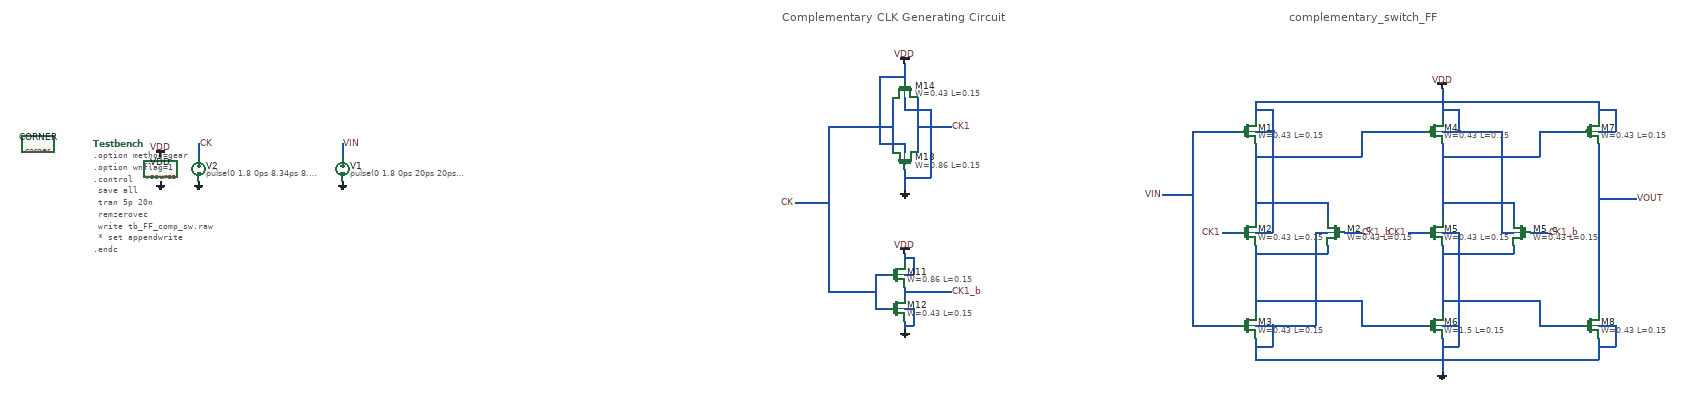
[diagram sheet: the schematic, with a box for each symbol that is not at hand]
v {xschem version=3.4.5 file_version=1.2
}
G {}
K {}
V {}
S {}
E {}
B 2 80 -1250 1130 -1020 {flags=graph
y1=0
y2=1.8
ypos1=0
ypos2=2
divy=5
subdivy=4
unity=1
x1=4.8339884e-10
x2=2.0666956e-09
divx=5
subdivx=4
xlabmag=1.0
ylabmag=1.0


dataset=-1
unitx=1
logx=0
logy=0











linewidth_mult=3





color=6
node=ck}
B 2 80 -990 1130 -760 {flags=graph
y1=0
y2=1.8
ypos1=0
ypos2=2
divy=5
subdivy=4
unity=1
x1=4.8339884e-10
x2=2.0666956e-09
divx=5
subdivx=4
xlabmag=1.0
ylabmag=1.0


dataset=-1
unitx=1
logx=0
logy=0











linewidth_mult=2











color=12
node=vin}
B 2 80 -730 1130 -500 {flags=graph
y1=-0.34
y2=2.2
ypos1=0
ypos2=2
divy=5
subdivy=4
unity=1
x1=4.8339884e-10
x2=2.0666956e-09
divx=5
subdivx=4
xlabmag=1.0
ylabmag=1.0


dataset=-1
unitx=1
logx=0
logy=0











linewidth_mult=2









color=5
node=vout}
T {Complementary CLK Generating Circuit} 1890 -1740 0 0 0.8 0.8 {}
T {complementary_switch_FF} 3090 -1740 0 0 0.8 0.8 {}
N 510 -1430 510 -1400 {
lab=CK}
N 3820 -1530 3820 -1490 {
lab=VDD}
N 3820 -1460 3860 -1460 {
lab=VDD}
N 3860 -1510 3860 -1460 {
lab=VDD}
N 3820 -1510 3860 -1510 {
lab=VDD}
N 3820 -950 3860 -950 {
lab=GND}
N 3820 -970 3820 -920 {
lab=GND}
N 3820 -1000 3860 -1000 {
lab=GND}
N 3450 -1530 3450 -1490 {
lab=VDD}
N 3450 -1460 3490 -1460 {
lab=VDD}
N 3490 -1510 3490 -1460 {
lab=VDD}
N 3450 -1510 3490 -1510 {
lab=VDD}
N 3450 -1220 3490 -1220 {
lab=GND}
N 3490 -1220 3490 -950 {
lab=GND}
N 3450 -950 3490 -950 {
lab=GND}
N 3450 -970 3450 -920 {
lab=GND}
N 3450 -1000 3490 -1000 {
lab=GND}
N 3010 -1530 3010 -1490 {
lab=VDD}
N 3010 -1460 3050 -1460 {
lab=VDD}
N 3050 -1510 3050 -1460 {
lab=VDD}
N 3010 -1510 3050 -1510 {
lab=VDD}
N 3010 -1220 3050 -1220 {
lab=VDD}
N 3010 -950 3050 -950 {
lab=GND}
N 3010 -970 3010 -920 {
lab=GND}
N 3010 -1000 3050 -1000 {
lab=GND}
N 3050 -1460 3050 -1220 {
lab=VDD}
N 3680 -1460 3780 -1460 {
lab=#net1}
N 3680 -1000 3780 -1000 {
lab=#net2}
N 3450 -1400 3680 -1400 {
lab=#net1}
N 2860 -1460 2970 -1460 {
lab=VIN}
N 2860 -1460 2860 -1090 {
lab=VIN}
N 2930 -1220 2970 -1220 {
lab=CK1}
N 3050 -1000 3050 -950 {
lab=GND}
N 3680 -1060 3680 -1000 {
lab=#net2}
N 3450 -1060 3680 -1060 {
lab=#net2}
N 3260 -1000 3410 -1000 {
lab=#net3}
N 3260 -1060 3260 -1000 {
lab=#net3}
N 3010 -1060 3260 -1060 {
lab=#net3}
N 3260 -1460 3410 -1460 {
lab=#net4}
N 3260 -1460 3260 -1400 {
lab=#net4}
N 3010 -1400 3260 -1400 {
lab=#net4}
N 3680 -1460 3680 -1400 {
lab=#net1}
N 3860 -1000 3860 -950 {
lab=GND}
N 3620 -1290 3620 -1250 {
lab=#net1}
N 3450 -1290 3620 -1290 {
lab=#net1}
N 3620 -1190 3620 -1170 {
lab=#net2}
N 3450 -1170 3620 -1170 {
lab=#net2}
N 3590 -1220 3620 -1220 {
lab=VDD}
N 3590 -1460 3590 -1220 {
lab=VDD}
N 3490 -1460 3590 -1460 {
lab=VDD}
N 3180 -1290 3180 -1250 {
lab=#net4}
N 3010 -1290 3180 -1290 {
lab=#net4}
N 3180 -1190 3180 -1170 {
lab=#net3}
N 3150 -1220 3180 -1220 {
lab=GND}
N 3010 -1170 3180 -1170 {
lab=#net3}
N 3150 -1220 3150 -1000 {
lab=GND}
N 3050 -1000 3150 -1000 {
lab=GND}
N 3010 -1530 3820 -1530 {
lab=VDD}
N 3450 -1560 3450 -1530 {
lab=VDD}
N 3010 -920 3820 -920 {
lab=GND}
N 3450 -920 3450 -890 {
lab=GND}
N 3220 -1220 3260 -1220 {
lab=CK1_b}
N 3660 -1220 3700 -1220 {
lab=CK1_b}
N 3370 -1220 3410 -1220 {
lab=CK1}
N 2790 -1310 2860 -1310 {
lab=VIN}
N 2860 -1000 2970 -1000 {
lab=VIN}
N 2860 -1090 2860 -1000 {
lab=VIN}
N 3820 -1300 3910 -1300 {
lab=VOUT}
N 3010 -1430 3010 -1250 {
lab=#net4}
N 3010 -1190 3010 -1030 {
lab=#net3}
N 3450 -1430 3450 -1250 {
lab=#net1}
N 3450 -1190 3450 -1030 {
lab=#net2}
N 3820 -1430 3820 -1030 {
lab=VOUT}
N 2150 -1540 2150 -1410 {
lab=CK}
N 2210 -1540 2210 -1410 {
lab=CK1}
N 2180 -1080 2290 -1080 {
lab=#net5}
N 1920 -1290 2000 -1290 {
lab=CK}
N 2210 -1470 2290 -1470 {
lab=CK1}
N 2180 -1620 2180 -1580 {
lab=VDD}
N 2180 -1370 2180 -1320 {
lab=GND}
N 2180 -1540 2180 -1510 {
lab=GND}
N 2180 -1510 2240 -1510 {
lab=GND}
N 2240 -1510 2240 -1350 {
lab=GND}
N 2180 -1350 2240 -1350 {
lab=GND}
N 2180 -1430 2180 -1410 {
lab=VDD}
N 2120 -1430 2180 -1430 {
lab=VDD}
N 2120 -1590 2120 -1430 {
lab=VDD}
N 2120 -1590 2180 -1590 {
lab=VDD}
N 2180 -1090 2180 -1070 {
lab=#net5}
N 2110 -1120 2140 -1120 {
lab=CK}
N 2110 -1120 2110 -1040 {
lab=CK}
N 2110 -1040 2140 -1040 {
lab=CK}
N 2180 -1010 2180 -990 {
lab=GND}
N 2180 -1040 2200 -1040 {
lab=GND}
N 2200 -1040 2200 -1000 {
lab=GND}
N 2180 -1000 2200 -1000 {
lab=GND}
N 2180 -1170 2180 -1150 {
lab=VDD}
N 2180 -1160 2200 -1160 {
lab=VDD}
N 2200 -1160 2200 -1120 {
lab=VDD}
N 2180 -1120 2200 -1120 {
lab=VDD}
N 2000 -1470 2150 -1470 {
lab=CK}
N 2000 -1470 2000 -1080 {
lab=CK}
N 2000 -1080 2110 -1080 {
lab=CK}
N 850 -1430 850 -1400 {
lab=VIN}
C {devices/vsource.sym} 420 -1370 0 0 {name=VDD value=1.8 savecurrent=false}
C {devices/gnd.sym} 420 -1340 0 0 {name=l1 lab=GND}
C {devices/code.sym} 260 -1430 0 0 {name=Testbench only_toplevel=false value="

.option method=gear
.option wnflag=1

.control

  save all
  tran 5p 20n
  remzerovec
  write tb_FF_comp_sw.raw
  * set appendwrite

.endc

"}
C {sky130_fd_pr/corner.sym} 130 -1430 0 0 {name=CORNER only_toplevel=false corner=tt}
C {devices/vdd.sym} 420 -1400 0 0 {name=l6 lab=VDD}
C {devices/gnd.sym} 510 -1340 0 0 {name=l16 lab=GND}
C {devices/lab_pin.sym} 510 -1430 0 1 {name=p19 sig_type=std_logic lab=CK}
C {devices/vsource.sym} 510 -1370 0 0 {name=V2 value="pulse(0 1.8 0ps 8.34ps 8.34ps 200.16ps 417ps)" savecurrent=false
* "pulse(0 1.8 12.5ns 0.5ns 0.5ns 12ns 25ns)"
* "pulse(0 1.8 0ps 16.68ps 16.68ps 408.32ps 834ps)"
* "pulse(0 1.8 0ps 20ps 20ps 480ps 1000ps)"}
C {devices/gnd.sym} 3450 -890 0 0 {name=l2 lab=GND}
C {devices/vdd.sym} 3450 -1560 0 0 {name=l3 lab=VDD}
C {sky130_fd_pr/pfet_01v8.sym} 3800 -1460 0 0 {name=M7
L=0.15
W=0.43
nf=1
mult=1
ad="'int((nf+1)/2) * W/nf * 0.29'" 
pd="'2*int((nf+1)/2) * (W/nf + 0.29)'"
as="'int((nf+2)/2) * W/nf * 0.29'" 
ps="'2*int((nf+2)/2) * (W/nf + 0.29)'"
nrd="'0.29 / W'" nrs="'0.29 / W'"
sa=0 sb=0 sd=0
model=pfet_01v8
spiceprefix=X
}
C {sky130_fd_pr/nfet_01v8.sym} 3430 -1220 0 0 {name=M5
L=0.15
W=0.43
nf=1 
mult=1
ad="'int((nf+1)/2) * W/nf * 0.29'" 
pd="'2*int((nf+1)/2) * (W/nf + 0.29)'"
as="'int((nf+2)/2) * W/nf * 0.29'" 
ps="'2*int((nf+2)/2) * (W/nf + 0.29)'"
nrd="'0.29 / W'" nrs="'0.29 / W'"
sa=0 sb=0 sd=0
model=nfet_01v8
spiceprefix=X
}
C {sky130_fd_pr/nfet_01v8.sym} 3800 -1000 0 0 {name=M8
L=0.15
W=0.43
nf=1 
mult=1
ad="'int((nf+1)/2) * W/nf * 0.29'" 
pd="'2*int((nf+1)/2) * (W/nf + 0.29)'"
as="'int((nf+2)/2) * W/nf * 0.29'" 
ps="'2*int((nf+2)/2) * (W/nf + 0.29)'"
nrd="'0.29 / W'" nrs="'0.29 / W'"
sa=0 sb=0 sd=0
model=nfet_01v8
spiceprefix=X
}
C {sky130_fd_pr/pfet_01v8.sym} 3430 -1460 0 0 {name=M4
L=0.15
W=0.43
nf=1
mult=1
ad="'int((nf+1)/2) * W/nf * 0.29'" 
pd="'2*int((nf+1)/2) * (W/nf + 0.29)'"
as="'int((nf+2)/2) * W/nf * 0.29'" 
ps="'2*int((nf+2)/2) * (W/nf + 0.29)'"
nrd="'0.29 / W'" nrs="'0.29 / W'"
sa=0 sb=0 sd=0
model=pfet_01v8
spiceprefix=X
}
C {sky130_fd_pr/nfet_01v8.sym} 3430 -1000 0 0 {name=M6
L=0.15
W=1.5
nf=1 
mult=1
ad="'int((nf+1)/2) * W/nf * 0.29'" 
pd="'2*int((nf+1)/2) * (W/nf + 0.29)'"
as="'int((nf+2)/2) * W/nf * 0.29'" 
ps="'2*int((nf+2)/2) * (W/nf + 0.29)'"
nrd="'0.29 / W'" nrs="'0.29 / W'"
sa=0 sb=0 sd=0
model=nfet_01v8
spiceprefix=X
}
C {sky130_fd_pr/pfet_01v8.sym} 2990 -1460 0 0 {name=M1
L=0.15
W=0.43
nf=1
mult=1
ad="'int((nf+1)/2) * W/nf * 0.29'" 
pd="'2*int((nf+1)/2) * (W/nf + 0.29)'"
as="'int((nf+2)/2) * W/nf * 0.29'" 
ps="'2*int((nf+2)/2) * (W/nf + 0.29)'"
nrd="'0.29 / W'" nrs="'0.29 / W'"
sa=0 sb=0 sd=0
model=pfet_01v8
spiceprefix=X
}
C {sky130_fd_pr/nfet_01v8.sym} 2990 -1000 0 0 {name=M3
L=0.15
W=0.43
nf=1 
mult=1
ad="'int((nf+1)/2) * W/nf * 0.29'" 
pd="'2*int((nf+1)/2) * (W/nf + 0.29)'"
as="'int((nf+2)/2) * W/nf * 0.29'" 
ps="'2*int((nf+2)/2) * (W/nf + 0.29)'"
nrd="'0.29 / W'" nrs="'0.29 / W'"
sa=0 sb=0 sd=0
model=nfet_01v8
spiceprefix=X
}
C {sky130_fd_pr/pfet_01v8.sym} 2990 -1220 0 0 {name=M2
L=0.15
W=0.43
nf=1
mult=1
ad="'int((nf+1)/2) * W/nf * 0.29'" 
pd="'2*int((nf+1)/2) * (W/nf + 0.29)'"
as="'int((nf+2)/2) * W/nf * 0.29'" 
ps="'2*int((nf+2)/2) * (W/nf + 0.29)'"
nrd="'0.29 / W'" nrs="'0.29 / W'"
sa=0 sb=0 sd=0
model=pfet_01v8
spiceprefix=X
}
C {sky130_fd_pr/pfet_01v8.sym} 3640 -1220 0 1 {name=M5_c
L=0.15
W=0.43
nf=1
mult=1
ad="'int((nf+1)/2) * W/nf * 0.29'" 
pd="'2*int((nf+1)/2) * (W/nf + 0.29)'"
as="'int((nf+2)/2) * W/nf * 0.29'" 
ps="'2*int((nf+2)/2) * (W/nf + 0.29)'"
nrd="'0.29 / W'" nrs="'0.29 / W'"
sa=0 sb=0 sd=0
model=pfet_01v8
spiceprefix=X
}
C {sky130_fd_pr/nfet_01v8.sym} 3200 -1220 0 1 {name=M2_c
L=0.15
W=0.43
nf=1 
mult=1
ad="'int((nf+1)/2) * W/nf * 0.29'" 
pd="'2*int((nf+1)/2) * (W/nf + 0.29)'"
as="'int((nf+2)/2) * W/nf * 0.29'" 
ps="'2*int((nf+2)/2) * (W/nf + 0.29)'"
nrd="'0.29 / W'" nrs="'0.29 / W'"
sa=0 sb=0 sd=0
model=nfet_01v8
spiceprefix=X
}
C {devices/lab_pin.sym} 3910 -1300 0 1 {name=p17 sig_type=std_logic lab=VOUT}
C {devices/lab_pin.sym} 2930 -1220 0 0 {name=p18 sig_type=std_logic lab=CK1}
C {devices/lab_pin.sym} 3370 -1220 0 0 {name=p2 sig_type=std_logic lab=CK1}
C {devices/lab_pin.sym} 3260 -1220 0 1 {name=p20 sig_type=std_logic lab=CK1_b}
C {devices/lab_pin.sym} 3700 -1220 0 1 {name=p21 sig_type=std_logic lab=CK1_b}
C {sky130_fd_pr/pfet_01v8.sym} 2180 -1390 3 0 {name=M13
L=0.15
W=0.86
nf=2
mult=1
ad="'int((nf+1)/2) * W/nf * 0.29'" 
pd="'2*int((nf+1)/2) * (W/nf + 0.29)'"
as="'int((nf+2)/2) * W/nf * 0.29'" 
ps="'2*int((nf+2)/2) * (W/nf + 0.29)'"
nrd="'0.29 / W'" nrs="'0.29 / W'"
sa=0 sb=0 sd=0
model=pfet_01v8
spiceprefix=X
}
C {sky130_fd_pr/nfet_01v8.sym} 2180 -1560 1 0 {name=M14
L=0.15
W=0.43
nf=1 
mult=1
ad="'int((nf+1)/2) * W/nf * 0.29'" 
pd="'2*int((nf+1)/2) * (W/nf + 0.29)'"
as="'int((nf+2)/2) * W/nf * 0.29'" 
ps="'2*int((nf+2)/2) * (W/nf + 0.29)'"
nrd="'0.29 / W'" nrs="'0.29 / W'"
sa=0 sb=0 sd=0
model=nfet_01v8
spiceprefix=X
}
C {devices/lab_pin.sym} 2290 -1080 0 1 {name=p22 sig_type=std_logic lab=CK1_b}
C {devices/lab_pin.sym} 2290 -1470 0 1 {name=p24 sig_type=std_logic lab=CK1}
C {devices/lab_pin.sym} 1920 -1290 0 0 {name=p3 sig_type=std_logic lab=CK}
C {sky130_fd_pr/pfet_01v8.sym} 2160 -1120 0 0 {name=M11
L=0.15
W=0.86
nf=2
mult=1
ad="'int((nf+1)/2) * W/nf * 0.29'" 
pd="'2*int((nf+1)/2) * (W/nf + 0.29)'"
as="'int((nf+2)/2) * W/nf * 0.29'" 
ps="'2*int((nf+2)/2) * (W/nf + 0.29)'"
nrd="'0.29 / W'" nrs="'0.29 / W'"
sa=0 sb=0 sd=0
model=pfet_01v8
spiceprefix=X
}
C {sky130_fd_pr/nfet_01v8.sym} 2160 -1040 0 0 {name=M12
L=0.15
W=0.43
nf=1 
mult=1
ad="'int((nf+1)/2) * W/nf * 0.29'" 
pd="'2*int((nf+1)/2) * (W/nf + 0.29)'"
as="'int((nf+2)/2) * W/nf * 0.29'" 
ps="'2*int((nf+2)/2) * (W/nf + 0.29)'"
nrd="'0.29 / W'" nrs="'0.29 / W'"
sa=0 sb=0 sd=0
model=nfet_01v8
spiceprefix=X
}
C {devices/vdd.sym} 2180 -1170 0 0 {name=l7 lab=VDD}
C {devices/gnd.sym} 2180 -990 0 0 {name=l8 lab=GND}
C {devices/gnd.sym} 2180 -1320 0 0 {name=l11 lab=GND}
C {devices/vdd.sym} 2180 -1620 0 0 {name=l12 lab=VDD}
C {devices/gnd.sym} 850 -1340 0 0 {name=l13 lab=GND}
C {devices/lab_pin.sym} 850 -1430 0 1 {name=p1 sig_type=std_logic lab=VIN}
C {devices/vsource.sym} 850 -1370 0 0 {name=V1 value="pulse(0 1.8 0ps 20ps 20ps 480ps 1000ps)" savecurrent=false
* "pulse(0 1.8 12.5ns 0.5ns 0.5ns 12ns 25ns)"
* "pulse(0 1.8 0ps 16.68ps 16.68ps 408.32ps 834ps)"}
C {devices/lab_pin.sym} 2790 -1310 0 0 {name=p4 sig_type=std_logic lab=VIN}
